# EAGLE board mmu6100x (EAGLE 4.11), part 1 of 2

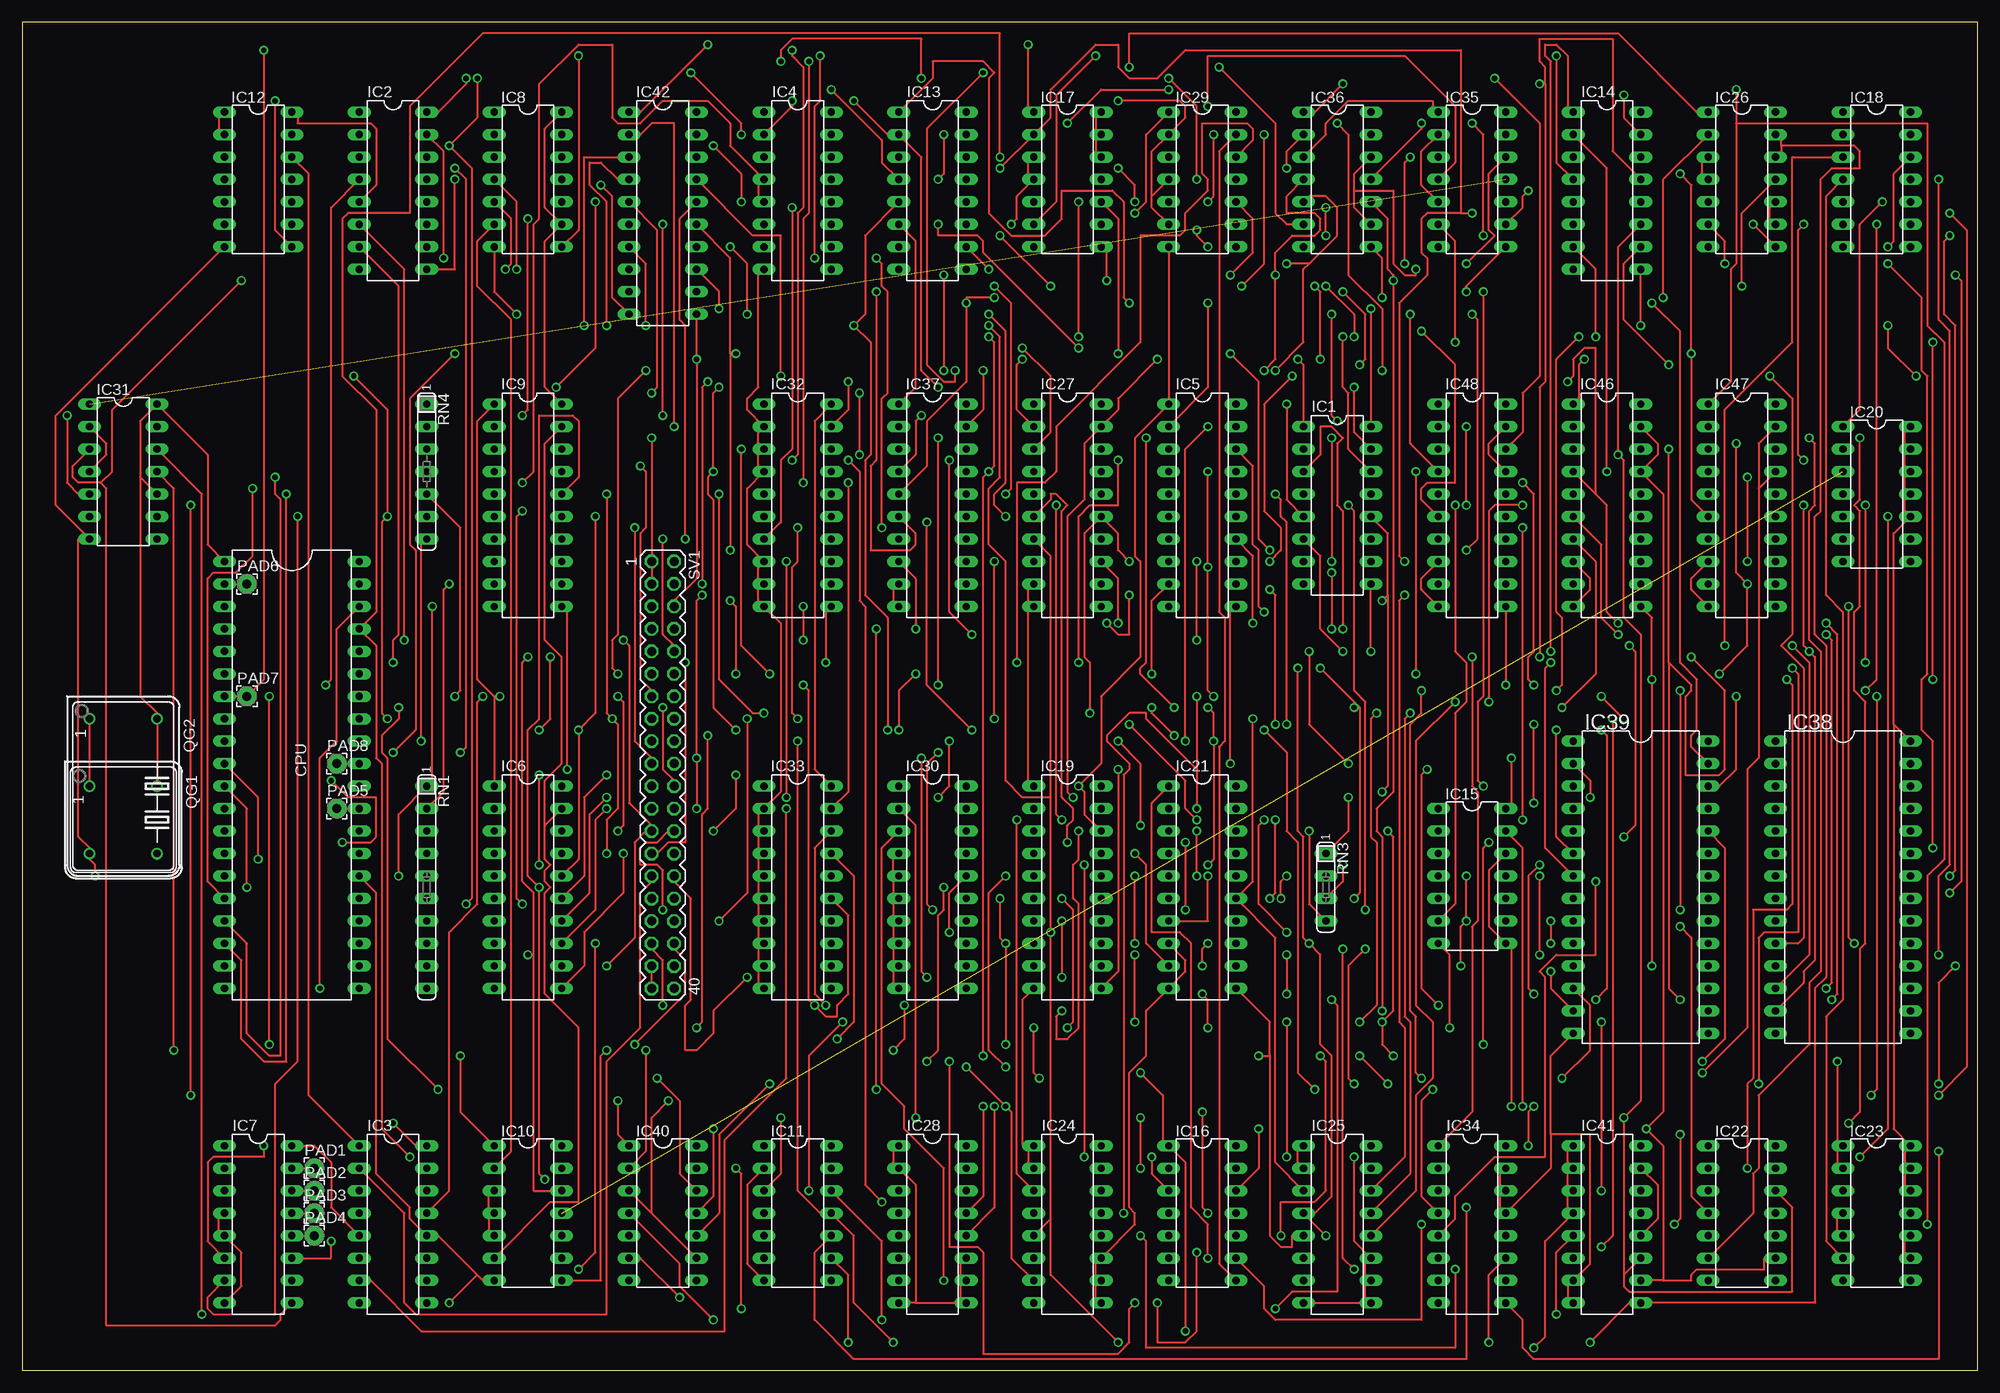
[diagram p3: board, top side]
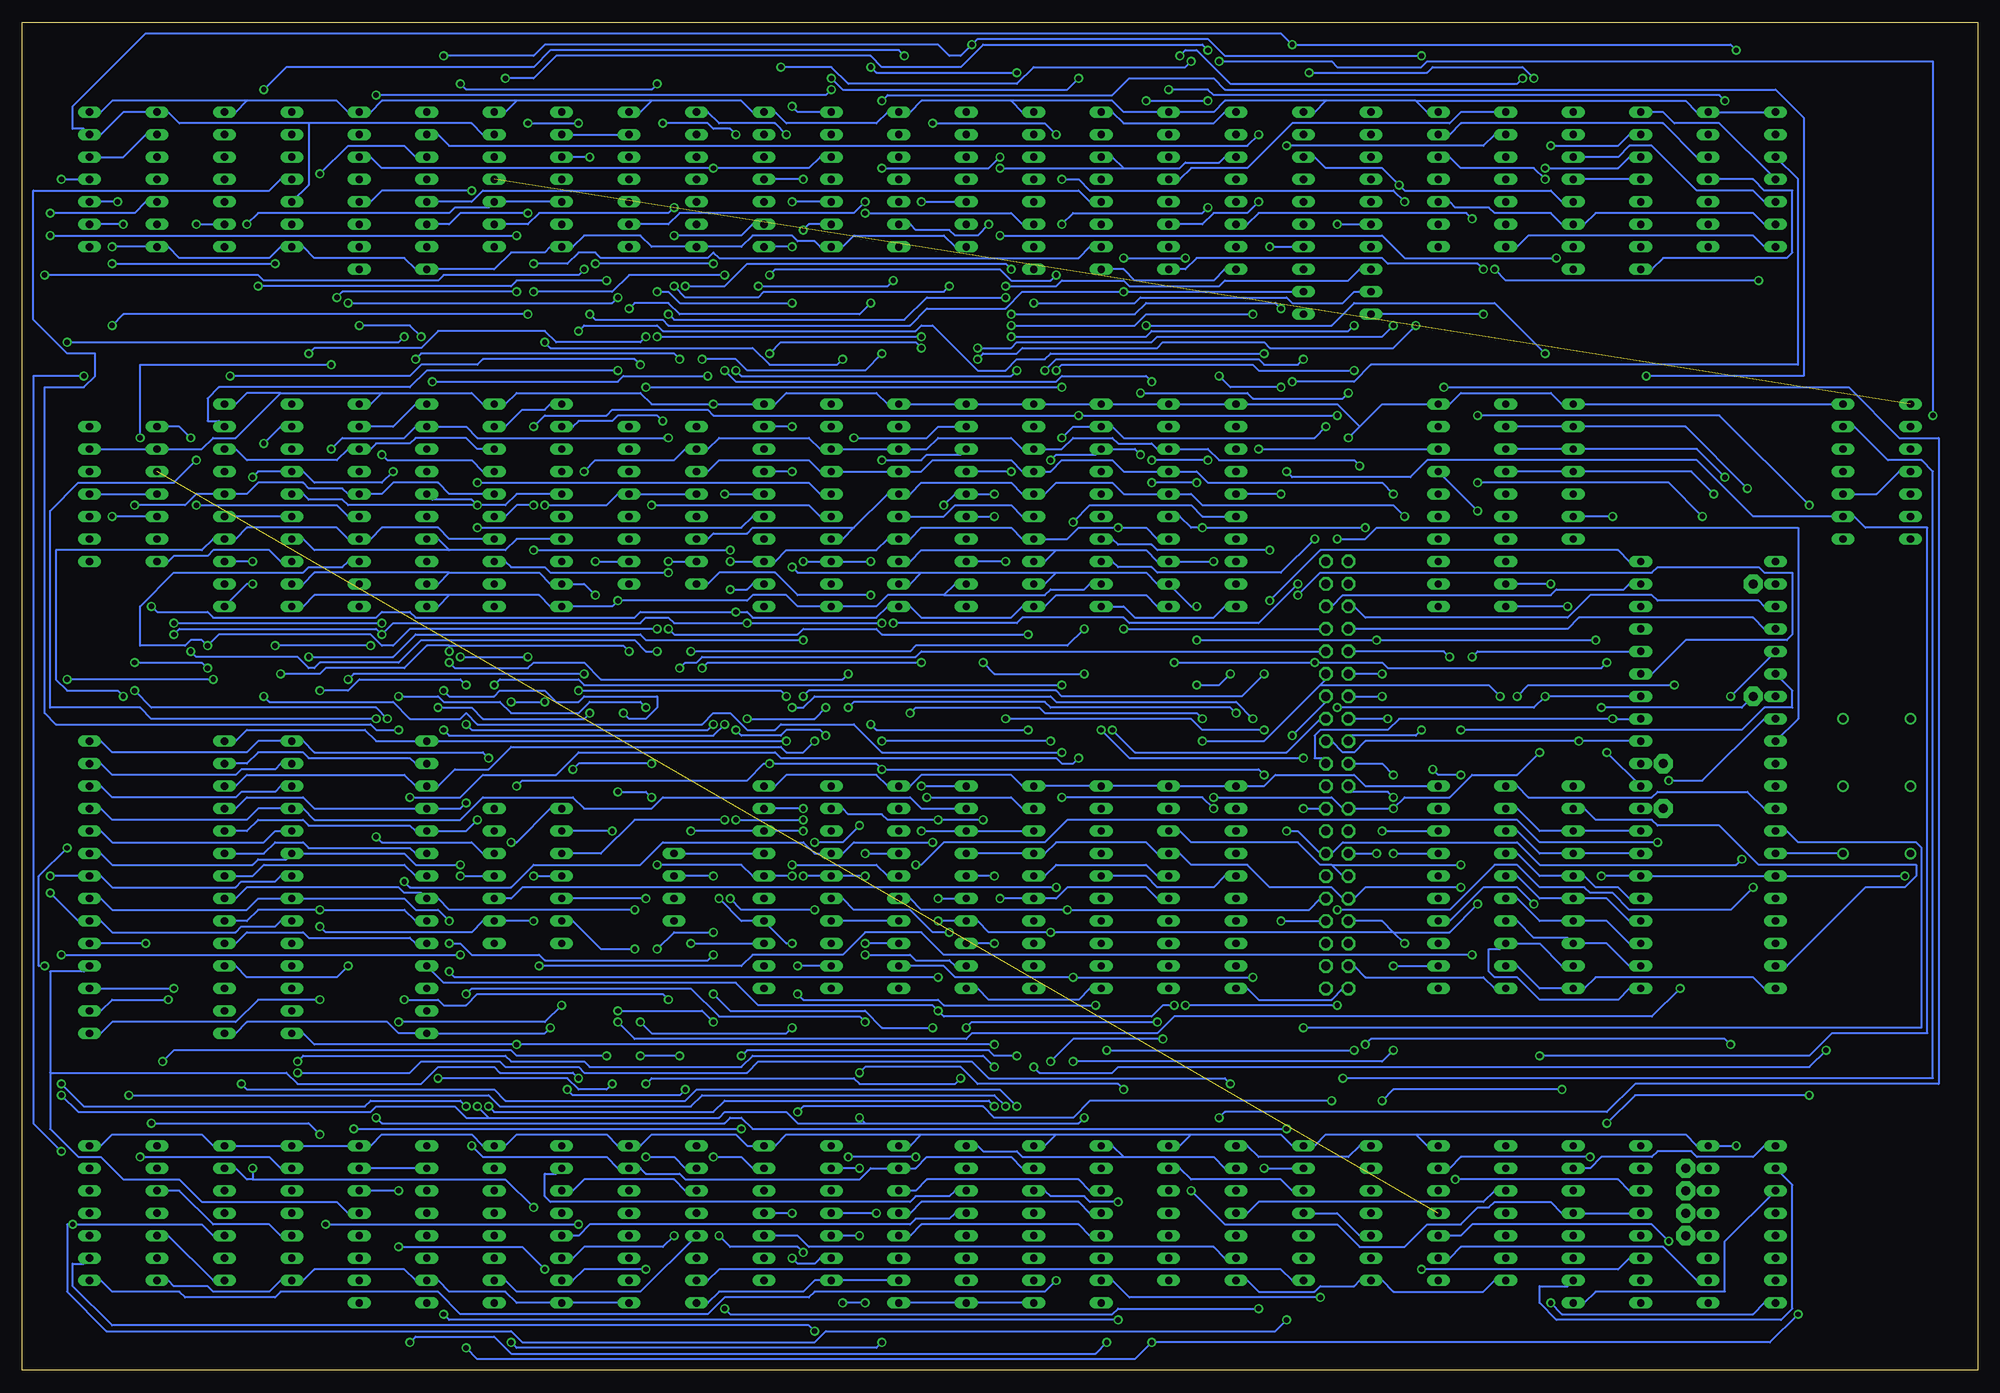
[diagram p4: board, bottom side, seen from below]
Size 220.98 x 152.4 mm. Coordinates in mm from the lower left corner, seen from the top.
Outline: 0,0 220.98,0 220.98,152.4 0,152.4 0,0
Copper layers (1*16): Top 0.035mm / dielectric 1.5mm / Bottom 0.035mm
Design rules "8mils": minimum track width 10mil, minimum drill 24mil, track to track 8mil, track to pad 8mil, pad to pad 8mil, via to via 8mil, smd to smd 8mil, copper to edge 40mil, drill to drill 10mil, minimum pad ring 10mil, minimum via ring 8mil, stop-mask expansion 0mil, vias tented up to drill 0mil, thermal gap 10mil

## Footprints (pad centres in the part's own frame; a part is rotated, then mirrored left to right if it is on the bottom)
DIL40 = drill 0.813 long: 1 -24.13,-7.62; 2 -21.59,-7.62; 3 -19.05,-7.62; 4 -16.51,-7.62; 5 -13.97,-7.62; 6 -11.43,-7.62; 7 -8.89,-7.62; 8 -6.35,-7.62; 9 -3.81,-7.62; 10 -1.27,-7.62; 11 1.27,-7.62; 12 3.81,-7.62; 13 6.35,-7.62; 14 8.89,-7.62; 15 11.43,-7.62; 16 13.97,-7.62; 17 16.51,-7.62; 18 19.05,-7.62; 19 21.59,-7.62; 20 24.13,-7.62; 21 24.13,7.62; 22 21.59,7.62; 23 19.05,7.62; 24 16.51,7.62; 25 13.97,7.62; 26 11.43,7.62; 27 8.89,7.62; 28 6.35,7.62; 29 3.81,7.62; 30 1.27,7.62; 31 -1.27,7.62; 32 -3.81,7.62; 33 -6.35,7.62; 34 -8.89,7.62; 35 -11.43,7.62; 36 -13.97,7.62; 37 -16.51,7.62; 38 -19.05,7.62; 39 -21.59,7.62; 40 -24.13,7.62
DIL16 = drill 0.813 long: 1 -8.89,-3.81; 2 -6.35,-3.81; 3 -3.81,-3.81; 4 -1.27,-3.81; 5 1.27,-3.81; 6 3.81,-3.81; 7 6.35,-3.81; 8 8.89,-3.81; 9 8.89,3.81; 10 6.35,3.81; 11 3.81,3.81; 12 1.27,3.81; 13 -1.27,3.81; 14 -3.81,3.81; 15 -6.35,3.81; 16 -8.89,3.81
DIL20 = drill 0.813 long: 1 -11.43,-3.81; 2 -8.89,-3.81; 3 -6.35,-3.81; 4 -3.81,-3.81; 5 -1.27,-3.81; 6 1.27,-3.81; 7 3.81,-3.81; 8 6.35,-3.81; 9 8.89,-3.81; 10 11.43,-3.81; 11 11.43,3.81; 12 8.89,3.81; 13 6.35,3.81; 14 3.81,3.81; 15 1.27,3.81; 16 -1.27,3.81; 17 -3.81,3.81; 18 -6.35,3.81; 19 -8.89,3.81; 20 -11.43,3.81
DIL14 = drill 0.813 long: 1 -7.62,-3.81; 2 -5.08,-3.81; 3 -2.54,-3.81; 4 0,-3.81; 5 2.54,-3.81; 6 5.08,-3.81; 7 7.62,-3.81; 8 7.62,3.81; 9 5.08,3.81; 10 2.54,3.81; 11 0,3.81; 12 -2.54,3.81; 13 -5.08,3.81; 14 -7.62,3.81
DIL28-6 = drill 0.813 long: 1 -16.51,-7.62; 2 -13.97,-7.62; 3 -11.43,-7.62; 4 -8.89,-7.62; 5 -6.35,-7.62; 6 -3.81,-7.62; 7 -1.27,-7.62; 8 1.27,-7.62; 9 3.81,-7.62; 10 6.35,-7.62; 11 8.89,-7.62; 12 11.43,-7.62; 13 13.97,-7.62; 14 16.51,-7.62; 15 16.51,7.62; 16 13.97,7.62; 17 11.43,7.62; 18 8.89,7.62; 19 6.35,7.62; 20 3.81,7.62; 21 1.27,7.62; 22 -1.27,7.62; 23 -3.81,7.62; 24 -6.35,7.62; 25 -8.89,7.62; 26 -11.43,7.62; 27 -13.97,7.62; 28 -16.51,7.62
2,15/1,0 = drill 1.016 pad 2.159 octagon: 1 0,0
DIL08S = drill 0.813 round: 1 -3.81,-3.81; 4 3.81,-3.81; 5 3.81,3.81; 8 -3.81,3.81
DIL14S = drill 0.813 round: 1 -7.62,-3.81; 7 7.62,-3.81; 8 7.62,3.81; 14 -7.62,3.81
SIL10 = drill 0.813 long: 1 -11.43,0; 2 -8.89,0; 3 -6.35,0; 4 -3.81,0; 5 -1.27,0; 6 1.27,0; 7 3.81,0; 8 6.35,0; 9 8.89,0; 10 11.43,0
SIL4 = drill 0.813 long: 1 -3.81,0; 2 -1.27,0; 3 1.27,0; 4 3.81,0
SIL7 = drill 0.813 long: 1 -7.62,0; 2 -5.08,0; 3 -2.54,0; 4 0,0; 5 2.54,0; 6 5.08,0; 7 7.62,0
MA20-2 = drill 1.016 octagon: 1 -24.13,-1.27; 2 -24.13,1.27; 3 -21.59,-1.27; 4 -21.59,1.27; 5 -19.05,-1.27; 6 -19.05,1.27; 7 -16.51,-1.27; 8 -16.51,1.27; 9 -13.97,-1.27; 10 -13.97,1.27; 11 -11.43,-1.27; 12 -11.43,1.27; 13 -8.89,-1.27; 14 -8.89,1.27; 15 -6.35,-1.27; 16 -6.35,1.27; 17 -3.81,-1.27; 18 -3.81,1.27; 19 -1.27,-1.27; 20 -1.27,1.27; 21 1.27,-1.27; 22 1.27,1.27; 23 3.81,-1.27; 24 3.81,1.27; 25 6.35,-1.27; 26 6.35,1.27; 27 8.89,-1.27; 28 8.89,1.27; 29 11.43,-1.27; 30 11.43,1.27; 31 13.97,-1.27; 32 13.97,1.27; 33 16.51,-1.27; 34 16.51,1.27; 35 19.05,-1.27; 36 19.05,1.27; 37 21.59,-1.27; 38 21.59,1.27; 39 24.13,-1.27; 40 24.13,1.27

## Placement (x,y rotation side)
CPU  IM6100  [DIL40]  30.48,67.31 270 top
IC1  74LS75N  [DIL16]  148.59,97.79 270 top
IC2  74LS75N  [DIL16]  41.91,133.35 270 top
IC3  74LS75N  [DIL16]  41.91,16.51 270 top
IC4  74HCT138N  [DIL16]  87.63,133.35 270 top
IC5  74LS373N  [DIL20]  133.35,97.79 270 top
IC6  74LS245N  [DIL20]  57.15,54.61 270 top
IC7  74HCT138N  [DIL16]  26.67,16.51 270 top
IC8  [DIL14]  57.15,134.62 270 top
IC9  74LS245N  [DIL20]  57.15,97.79 270 top
IC10  74HCT00N  [DIL14]  57.15,17.78 270 top
IC11  74LS74N  [DIL14]  87.63,17.78 270 top
IC12  74LS30N  [DIL14]  26.67,134.62 270 top
IC13  74HCT138N  [DIL16]  102.87,133.35 270 top
IC14  74HCT138N  [DIL16]  179.07,133.35 270 top
IC15  74HCT08N  [DIL14]  163.83,55.88 270 top
IC16  74LS32N  [DIL14]  133.35,17.78 270 top
IC17  74LS32N  [DIL14]  118.11,134.62 270 top
IC18  74LS74N  [DIL14]  209.55,134.62 270 top
IC19  74LS373N  [DIL20]  118.11,54.61 270 top
IC20  74LS74N  [DIL14]  209.55,99.06 270 top
IC21  74LS241N  [DIL20]  133.35,54.61 270 top
IC22  [DIL14]  194.31,17.78 270 top
IC23  74HCT00N  [DIL14]  209.55,17.78 270 top
IC24  74LS173N  [DIL16]  118.11,16.51 270 top
IC25  74LS173N  [DIL16]  148.59,16.51 270 top
IC26  74HCT00N  [DIL14]  194.31,134.62 270 top
IC27  74LS245N  [DIL20]  118.11,97.79 270 top
IC28  74LS173N  [DIL16]  102.87,16.51 270 top
IC29  74LS07N  [DIL14]  133.35,134.62 270 top
IC30  74LS245N  [DIL20]  102.87,54.61 270 top
IC31  74LS74N  [DIL14]  11.43,101.6 270 top
IC32  74LS245N  [DIL20]  87.63,97.79 270 top
IC33  74LS245N  [DIL20]  87.63,54.61 270 top
IC34  74LS157N  [DIL16]  163.83,16.51 270 top
IC35  74LS32N  [DIL14]  163.83,134.62 270 top
IC36  74HCT08N  [DIL14]  148.59,134.62 270 top
IC37  74LS245N  [DIL20]  102.87,97.79 270 top
IC38  [DIL28-6]  205.74,54.61 270 top
IC39  [DIL28-6]  182.88,54.61 270 top
IC40  74LS11N  [DIL14]  72.39,17.78 270 top
IC41  74LS151N  [DIL16]  179.07,16.51 270 top
IC42  74LS273N  [DIL20]  72.39,130.81 270 top
IC46  74LS244N  [DIL20]  179.07,97.79 270 top
IC47  74LS244N  [DIL20]  194.31,97.79 270 top
IC48  74LS244N  [DIL20]  163.83,97.79 270 top
PAD1  [2,15/1,0]  33.02,22.86 0 top
PAD2  [2,15/1,0]  33.02,20.32 0 top
PAD3  [2,15/1,0]  33.02,17.78 0 top
PAD4  [2,15/1,0]  33.02,15.24 0 top
PAD5  [2,15/1,0]  35.56,63.5 0 top
PAD6  [2,15/1,0]  25.4,88.9 0 top
PAD7  [2,15/1,0]  25.4,76.2 0 top
PAD8  [2,15/1,0]  35.56,68.58 0 top
QG1  [DIL08S]  11.43,62.23 270 top
QG2  [DIL14S]  11.43,66.04 270 top
RN1  100K  [SIL10]  45.72,54.61 270 top
RN3  100K  [SIL4]  147.32,54.61 270 top
RN4  [SIL7]  45.72,101.6 270 top
SV1  [MA20-2]  72.39,67.31 270 top

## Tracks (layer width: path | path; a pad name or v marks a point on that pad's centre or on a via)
00\  (via drill 0.61)
  Top 0.254: v28.57,143.51 28.57,128.91 IC12.8 | v91.44,144.78 97.16,139.06 97.16,136.53 IC13.4
  Bottom 0.254: v28.57,143.51 29.21,144.15 86.36,144.15 87,144.78 v91.44,144.78
2X\  (via drill 0.61)
  Top 0.254: v62.87,148.59 62.87,128.91 IC8.8 | v113.67,149.86 113.67,142.88 IC17.1 | v173.35,148.59 173.35,136.53 IC14.4
  Bottom 0.254: v62.87,148.59 85.09,148.59 87,150.5 113.03,150.5 v113.67,149.86 114.94,148.59 116.2,148.59 117.47,149.86 161.93,149.86 163.19,148.59 v173.35,148.59
AND\
  Top 0.254: IC7.15 PAD1.1
BFLD0
  Bottom 0.254: IC28.5 100.33,15.24 101.6,16.51 119.38,16.51 120.65,15.24 IC24.12
BFLD1
  Bottom 0.254: IC28.4 100.33,17.78 101.6,19.05 119.38,19.05 120.65,17.78 IC24.13
BFLD2
  Bottom 0.254: IC28.3 100.33,20.32 101.6,21.59 118.75,21.59 120.02,20.32 IC24.14
BFLOAD  (via drill 0.61)
  Top 0.254: v74.3,8.26 69.85,12.7 IC40.6
  Bottom 0.254: v74.3,8.26 95.89,8.26 97.79,10.16 IC28.7
BMUX0  (via drill 0.61)
  Top 0.254: v109.86,29.84 109.86,18.41 IC28.12 | v208.91,31.11 209.55,31.75 v209.55,76.2
  Bottom 0.254: IC48.14 172.72,93.98 173.99,95.25 180.34,95.25 181.61,93.98 IC46.14 184.15,93.98 185.42,95.25 195.58,95.25 196.85,93.98 IC47.14 199.39,93.98 200.66,92.71 217.17,92.71 217.17,78.11 215.9,76.83 210.19,76.83 v209.55,76.2 | v109.86,29.84 111.12,31.11 144.15,31.11 145.41,29.84 167,29.84 168.28,31.11 v208.91,31.11
BMUX1  (via drill 0.61)
  Top 0.254: v108.58,29.84 108.58,19.68 IC28.13 | v196.22,32.38 196.22,48.9 196.85,49.53 200.66,49.53 200.66,78.74 v200.03,79.38 | v208.28,97.79 v208.28,80.01
  Bottom 0.254: IC48.16 172.72,99.06 173.99,100.33 179.07,100.33 180.34,99.06 IC46.16 184.15,99.06 184.78,99.69 188.59,99.69 189.23,100.33 194.31,100.33 195.58,99.06 IC47.16 201.29,99.06 202.56,97.79 v208.28,97.79 | v108.58,29.84 110.49,31.75 144.78,31.75 146.05,30.48 166.37,30.48 167.64,31.75 195.58,31.75 v196.22,32.38 | v200.03,79.38 200.66,80.01 v208.28,80.01
BMUX2  (via drill 0.61)
  Top 0.254: v97.16,19.05 95.25,20.95 95.25,86.36 94.61,87 94.61,101.6 v93.34,102.87 | v87,102.87 87.63,103.5 87.63,130.81 88.27,131.44 88.27,147.32 87,148.59 v87,149.22 | v166.37,146.05 171.45,140.97 171.45,112.39 169.54,110.49 169.54,106.05 IC48.18
  Bottom 0.254: IC47.18 196.85,104.14 195.58,102.87 185.42,102.87 184.15,104.14 IC46.18 181.61,104.14 180.97,104.78 177.16,104.78 176.53,105.41 170.81,105.41 169.54,104.14 IC48.18 | v97.16,19.05 100.33,19.05 100.97,19.68 104.78,19.68 105.41,20.32 IC28.14 | v87,102.87 v93.34,102.87 | v87,149.22 87.63,149.86 112.39,149.86 114.94,147.32 123.83,147.32 125.09,148.59 160.66,148.59 163.19,146.05 v166.37,146.05
C0\  (via drill 0.61)
  Top 0.254: v45.09,71.12 45.09,93.34 RN4.7
  Bottom 0.254: CPU.32 v45.09,71.12 69.22,71.12 70.48,69.85 71.75,69.85 73.03,71.12 SV1.18
C1\  (via drill 0.61)
  Top 0.254: 127.64,132.72 127.64,131.44 IC29.6 | 127.64,132.72 IC29.4 | 127.64,132.72 127.64,137.79 IC29.2 131.44,141.6 131.44,142.88 130.81,143.51 v123.83,143.51 | v133.99,127 132.72,128.27 v132.72,128.91 | v41.27,73.66 40.64,74.3 40.64,95.89 v41.27,96.52 41.27,108.58 v37.47,112.39
  Bottom 0.254: v132.72,128.91 132.08,129.54 IC29.6 | v133.99,127 IC29.8 | CPU.33 v41.27,73.66 65.41,73.66 66.67,72.39 74.3,72.39 74.93,71.75 74.93,69.22 73.66,69.22 SV1.20 | v41.27,96.52 RN4.6 | v123.83,143.51 123.19,144.15 97.79,144.15 95.89,146.05 86.36,146.05 85.09,144.78 22.86,144.78 19.68,141.6 19.68,112.39 v37.47,112.39
C2\  (via drill 0.61)
  Top 0.254: v48.9,76.2 49.53,76.83 49.53,95.25 RN4.5 | v72.39,74.93 72.39,67.94 73.66,66.67 SV1.22
  Bottom 0.254: CPU.34 v48.9,76.2 50.16,74.93 v72.39,74.93
CAF\  (via drill 0.61)
  Top 0.254: v163.19,125.09 166.37,128.27 165.74,128.91 165.74,135.25 IC35.12
  Bottom 0.254: v163.19,125.09 159.38,125.09 158.12,126.36 156.21,126.36 155.57,125.73 143.51,125.73 142.88,126.36 142.24,125.73 101.6,125.73 100.33,127 IC13.7
CDF\  (via drill 0.61)
  Top 0.254: v84.45,32.38 78.74,26.67 78.74,17.78 IC40.10 | v189.87,33.66 194.94,38.73 194.94,67.94 196.22,69.22 196.22,99.69 | 196.22,99.69 IC47.17 | 196.22,99.69 196.22,104.78 IC47.19 | v122.56,123.19 122.56,126.36 IC17.8 | v137.79,122.56 140.34,125.09 v140.34,139.7 | v148.59,140.97 149.86,139.7 149.86,123.83 153.67,120.02 v153.67,113.03
  Bottom 0.254: v84.45,32.38 85.09,33.02 111.76,33.02 113.67,34.92 137.79,34.92 139.06,33.66 157.48,33.66 158.12,34.29 166.37,34.29 167,34.92 175.9,34.92 177.16,33.66 v189.87,33.66 | v122.56,123.19 123.19,122.56 v137.79,122.56 | v140.34,139.7 140.97,140.34 142.88,140.34 143.51,140.97 v148.59,140.97 | v153.67,113.03 175.26,113.03 177.16,111.12 198.75,111.12 200.03,109.86 200.03,107.31 198.75,107.31 IC47.19
CIF\  (via drill 0.61)
  Top 0.254: v193.68,144.78 193.68,140.97 | 193.68,140.97 193.68,125.09 193.04,124.46 193.04,111.76 IC47.1 | v121.28,148.59 116.84,144.15 116.84,132.08 IC17.6 | v78.11,5.71 74.3,9.53 74.3,12.06 IC40.4 | 193.68,140.97 215.26,140.97 215.26,118.11 217.17,116.2 217.17,57.78 215.26,55.88 v215.26,16.51
  Bottom 0.254: v193.68,144.78 191.13,147.32 163.19,147.32 161.29,149.22 121.92,149.22 v121.28,148.59 | v78.11,5.71 79.38,4.45 130.18,4.45 131.44,3.17 164.47,3.17 165.74,4.45 211.46,4.45 215.9,8.89 215.9,16.51 v215.26,16.51 200.66,16.51 199.39,15.24 IC22.10
CINT\  (via drill 0.61)
  Top 0.254: v85.72,28.57 85.72,22.23 IC11.3 | v60.33,111.12 64.77,115.57 v64.77,132.08 | v103.5,134.62 104.14,135.25 v104.14,139.7 | v118.11,140.97 121.92,144.78 v129.54,144.78 | v180.97,144.15 180.97,141.6 IC14.15
  Bottom 0.254: v85.72,28.57 85.09,29.21 41.91,29.21 38.73,32.38 4.45,32.38 4.45,105.41 8.89,105.41 14.61,111.12 v60.33,111.12 | v64.77,132.08 66.04,133.35 100.33,133.35 101.6,134.62 v103.5,134.62 | v104.14,139.7 105.41,140.97 v118.11,140.97 | v129.54,144.78 130.18,144.15 v180.97,144.15
CPREQ\  (via drill 0.61)
  Top 0.254: v27.94,36.83 v27.94,76.2 | v69.22,36.83 74.93,42.55 74.93,46.35 73.66,47.62 SV1.36
  Bottom 0.254: v27.94,36.83 28.57,37.47 68.58,37.47 v69.22,36.83 | v27.94,76.2 CPU.5
CPSEL
  Bottom 0.254: IC22.5 191.77,15.24 193.04,16.51 199.39,16.51 203.2,20.32 IC23.3
CPSEL\  (via drill 0.61)
  Top 0.254: IC23.2 205.1,23.5 205.1,24.77 IC23.1 205.1,26.04 v205.1,34.92 | v33.66,43.18 33.66,69.22 35.56,71.12 35.56,83.82 CPU.38 | v154.31,60.96 154.94,60.33 154.94,40.64 v153.67,39.37 153.67,36.83 v154.94,35.56
  Bottom 0.254: v33.66,43.18 36.83,40.01 90.81,40.01 92.71,38.1 113.67,38.1 114.3,37.47 151.76,37.47 v153.67,39.37 | v154.31,60.96 IC15.2 | v205.1,34.92 203.84,36.2 165.74,36.2 165.1,35.56 v154.94,35.56
CPUDX0  (via drill 0.61)
  Top 0.254: v26.04,99.69 26.04,92.08 24.13,90.17 21.59,90.17 20.95,89.53 20.95,55.24 CPU.16
  Bottom 0.254: v26.04,99.69 33.02,106.68 RN4.2 IC9.2
CPUDX1  (via drill 0.61)
  Top 0.254: v28.57,100.97 28.57,99.06 29.21,98.42 29.21,35.56 27.94,35.56 25.4,38.1 25.4,48.26 CPU.17
  Bottom 0.254: v28.57,100.97 31.75,104.14 RN4.3 IC9.3
CPUDX2  (via drill 0.61)
  Top 0.254: v29.84,99.06 29.84,34.92 27.3,34.92 24.77,37.47 24.77,46.35 CPU.18
  Bottom 0.254: v29.84,99.06 32.38,101.6 RN4.4 IC9.4
CPUDX3  (via drill 0.61)
  Top 0.254: v48.26,88.9 47.62,88.27 47.62,65.41 RN1.2
  Bottom 0.254: CPU.19 21.59,45.72 12.7,54.61 8.26,54.61 6.99,55.88 6.99,57.15 24.77,57.15 29.21,61.59 36.2,61.59 36.83,62.23 43.18,62.23 44.45,63.5 RN1.2 | v48.26,88.9 IC9.9
CPUDX4
  Bottom 0.254: CPU.20 24.13,43.18 25.4,44.45 43.18,44.45 44.45,43.18 RN1.10 49.53,43.18 52.07,45.72 IC6.9
CPUDX5
  Bottom 0.254: CPU.21 39.37,43.18 40.64,41.91 49.53,41.91 52.07,44.45 54.61,44.45 55.24,45.09 55.24,47.62 53.98,47.62 IC6.8 49.53,48.26 46.99,45.72 RN1.9
CPUDX6
  Bottom 0.254: CPU.22 39.37,45.72 41.91,48.26 RN1.8 46.35,48.9 50.16,48.9 52.07,50.8 IC6.7
CPUDX7
  Bottom 0.254: CPU.23 39.37,48.26 41.91,50.8 RN1.7 49.53,50.8 52.07,53.34 IC6.6
CPUDX8
  Bottom 0.254: CPU.24 39.37,50.8 41.91,53.34 RN1.6 49.53,53.34 52.07,55.88 IC6.5
CPUDX9
  Bottom 0.254: CPU.25 39.37,53.34 40.64,54.61 43.18,54.61 44.45,55.88 RN1.5 49.53,55.88 52.07,58.42 IC6.4
CPUDX10
  Bottom 0.254: CPU.27 RN1.4 49.53,58.42 52.07,60.96 IC6.3
CPUDX11
  Bottom 0.254: CPU.28 RN1.3 49.53,60.96 52.07,63.5 IC6.2
CPUINTREQ\  (via drill 0.61)
  Top 0.254: v34.92,66.67 36.83,64.77 40.01,64.77 40.01,60.33 39.37,59.69 v36.2,59.69 | v120.02,57.15 v120.02,24.13 | v127.64,24.13 127.64,22.23 IC16.3
  Bottom 0.254: v34.92,66.67 31.11,66.67 24.13,73.66 CPU.8 | v36.2,59.69 49.53,59.69 52.07,62.23 102.87,62.23 105.41,59.69 116.84,59.69 119.38,57.15 v120.02,57.15 | v120.02,24.13 v127.64,24.13
CUF\  (via drill 0.61)
  Top 0.254: v70.48,36.2 70.48,24.77 IC40.2 | v98.42,36.2 99.69,37.47 v99.69,41.27 | v133.35,42.55 133.99,41.91 v133.99,38.73 | v151.13,39.37 153.03,41.27 153.03,59.69 152.4,60.33 152.4,73.66 v153.03,74.3 | v173.35,76.83 173.99,77.47 173.99,85.09 173.35,85.72 173.35,114.3 v175.9,116.84 | v182.88,118.11 IC14.9
  Bottom 0.254: v98.42,36.2 v70.48,36.2 | v99.69,41.27 116.84,41.27 117.47,41.91 132.72,41.91 v133.35,42.55 | v133.99,38.73 134.62,38.1 149.86,38.1 v151.13,39.37 | v153.03,74.3 152.4,73.66 150.5,73.66 149.22,74.93 149.22,76.2 157.48,76.2 158.12,75.56 160.66,75.56 161.93,76.83 167,76.83 167.64,76.2 172.72,76.2 v173.35,76.83 | v175.9,116.84 177.16,118.11 v182.88,118.11
DATAF  (via drill 0.61)
  Top 0.254: v80.01,87 80.64,86.36 v80.64,78.74 | 132.72,67.94 v132.72,63.5 | v132.72,76.2 132.72,67.94 | v124.46,17.78 124.46,67.31 125.09,67.94 125.09,68.58 122.56,71.12 122.56,71.75 125.09,74.3 127,74.3 127,73.66 132.72,67.94
  Bottom 0.254: v80.01,87 74.3,92.71 40.64,92.71 39.37,91.44 CPU.40 | v80.64,78.74 83.19,76.2 103.5,76.2 104.14,76.83 132.08,76.83 v132.72,76.2 | v132.72,63.5 IC21.19 | v124.46,17.78 IC16.4
DCA\
  Top 0.254: IC7.12 PAD4.1
DEVINTREQ  (via drill 0.61)
  Top 0.254: v104.14,10.16 104.14,22.86 99.69,27.3 99.69,29.84 97.16,32.38 97.16,59.05 IC30.3
  Bottom 0.254: v104.14,10.16 105.41,8.89 131.44,8.89 132.08,8.26 141.6,8.26 143.51,6.35 171.45,6.35 173.99,8.89 191.77,8.89 192.41,8.26 202.56,8.26 203.2,8.89 210.82,8.89 212.09,10.16 IC23.8
DEVINTREQ\  (via drill 0.61)
  Top 0.254: IC23.9 212.72,13.34 212.72,14.61 IC23.10 | v131.44,4.45 131.44,23.5 IC16.1 128.91,26.04 128.91,31.11 v126.36,33.66 | v96.52,31.75 v96.52,83.82
  Bottom 0.254: v131.44,4.45 132.08,5.08 210.82,5.08 215.26,9.53 215.26,12.06 214,12.06 IC23.9 | v96.52,31.75 97.16,32.38 113.03,32.38 114.94,34.29 125.73,34.29 v126.36,33.66 | v96.52,83.82 SV1.8
DEVSEL\  (via drill 0.61)
  Top 0.254: v41.91,69.85 44.45,72.39 44.45,92.71 43.81,93.34 43.81,109.86 v48.9,114.94 | IC13.5 95.25,128.27 95.25,119.38 v93.98,118.11 95.89,116.2 95.89,103.5 95.25,102.87 95.25,87.63 97.79,85.09 v97.79,72.39
  Bottom 0.254: v48.9,114.94 54.61,120.65 70.48,120.65 73.03,118.11 v93.98,118.11 | v41.91,69.85 CPU.30 | IC14.5 170.18,132.08 168.91,133.35 101.6,133.35 100.33,132.08 IC13.5 | v97.79,72.39 95.25,69.85 78.11,69.85 74.3,73.66 SV1.16
DFLD0  (via drill 0.61)
  Top 0.254: 140.97,35.56 140.97,15.24 142.24,13.97 143.51,13.97 143.51,15.24 IC25.5 | 140.97,35.56 140.97,39.37 IC21.11 | v70.48,118.11 70.48,125.09 IC42.7 | v109.22,116.84 109.86,116.2 109.86,102.23 v109.22,101.6 108.58,100.97 v108.58,35.56 | v139.7,35.56 140.97,35.56
  Bottom 0.254: IC25.5 151.13,8.89 165.1,8.89 166.37,10.16 IC34.10 | v70.48,118.11 71.12,117.47 93.34,117.47 93.98,116.84 v109.22,116.84 | v109.22,101.6 IC27.4 | v139.7,35.56 139.06,36.2 111.76,36.2 111.12,35.56 v108.58,35.56
DFLD1  (via drill 0.61)
  Top 0.254: v147.32,15.24 IC25.4 146.05,17.78 147.96,19.68 147.96,35.56 146.69,36.83 146.69,46.99 v145.41,48.26 144.78,48.9 144.78,60.33 144.15,60.96 v144.15,79.38 | v66.04,118.11 66.04,132.08 64.14,133.99 64.14,136.53 65.41,136.53 67.31,134.62 IC42.4 | v113.03,115.57 116.2,112.39 116.2,106.05 IC27.3 | v119.38,80.01 119.38,96.52 120.65,97.79 123.83,97.79 v123.83,102.87
  Bottom 0.254: v147.32,15.24 148.59,13.97 157.48,13.97 158.75,12.7 IC34.6 | v145.41,48.26 IC21.13 | v66.04,118.11 67.31,116.84 92.71,116.84 93.34,116.2 108.58,116.2 109.22,115.57 v113.03,115.57 | v144.15,79.38 143.51,80.01 v119.38,80.01 | v123.83,102.87 119.38,102.87 118.75,103.5 114.94,103.5 IC27.3
DFLD2  (via drill 0.61)
  Top 0.254: IC25.3 141.6,23.5 141.6,48.9 IC21.15 139.06,55.24 v139.06,73.66 | v63.5,118.11 63.5,137.16 IC42.3 | v113.03,114.3 112.39,113.67 112.39,108.58 IC27.2 | v130.18,74.93 126.36,78.74 126.36,79.38 127,80.01 v127,105.41
  Bottom 0.254: IC25.3 146.05,20.32 147.32,21.59 157.48,21.59 158.75,20.32 IC34.3 | v63.5,118.11 66.04,115.57 80.01,115.57 80.64,116.2 92.08,116.2 92.71,115.57 107.95,115.57 108.58,114.94 112.39,114.94 v113.03,114.3 | v139.06,73.66 131.44,73.66 v130.18,74.93 | v127,105.41 118.75,105.41 117.47,106.68 IC27.2
DFLOAD
  Bottom 0.254: IC40.8 77.47,10.16 78.74,11.43 142.24,11.43 143.51,10.16 IC25.7
DMAGNT
  Bottom 0.254: CPU.3 24.13,86.36 24.77,87 36.2,87 36.83,87.63 43.81,87.63 46.35,85.09 69.22,85.09 70.48,86.36 SV1.5
DMAREQ\
  Bottom 0.254: CPU.4 24.13,83.82 25.4,85.09 45.09,85.09 46.35,83.82 SV1.7
DMUX0  (via drill 0.61)
  Top 0.254: v161.93,75.56 157.48,71.12 157.48,41.27 159.38,39.37 159.38,33.02 157.48,31.11 157.48,20.32 IC25.12 | v165.74,75.56 165.74,97.16 166.37,97.79 v169.54,97.79
  Bottom 0.254: v165.74,75.56 v161.93,75.56 | v169.54,97.79 170.18,98.42 174.62,98.42 IC46.5 | v169.54,97.79 166.37,97.79 165.1,99.06 IC48.5 | v169.54,97.79 184.15,97.79 184.78,98.42 188.59,98.42 189.23,99.06 IC47.5
DMUX1  (via drill 0.61)
  Top 0.254: v156.84,74.3 156.21,73.66 156.21,40.01 156.84,39.37 156.84,22.23 IC25.13 | v173.99,74.93 177.8,78.74 177.8,91.44 IC46.7
  Bottom 0.254: v156.84,74.3 157.48,73.66 168.91,73.66 170.18,74.93 v173.99,74.93 | 172.72,92.71 166.37,92.71 165.1,93.98 IC48.7 | 172.72,92.71 173.99,93.98 IC46.7 | 172.72,92.71 187.96,92.71 189.23,93.98 IC47.7
DMUX2  (via drill 0.61)
  Top 0.254: v156.21,87.63 155.57,87 155.57,39.37 156.21,38.73 156.21,24.13 IC25.14
  Bottom 0.254: v156.21,87.63 157.48,88.9 IC48.9 161.29,88.9 162.56,90.17 172.72,90.17 | 172.72,90.17 173.99,88.9 IC46.9 | 172.72,90.17 187.96,90.17 189.23,88.9 IC47.9
DORTF\  (via drill 0.61)
  Top 0.254: IC40.9 71.12,17.78 | 71.12,17.78 IC40.3 | v133.99,17.78 133.35,18.41 v133.35,29.21 | v73.03,30.48 71.12,28.57 71.12,17.78
  Bottom 0.254: v133.35,29.21 132.72,29.84 112.39,29.84 111.12,28.57 102.23,28.57 100.33,30.48 v73.03,30.48 | v133.99,17.78 IC16.11
DX0  (via drill 0.61)
  Top 0.254: v110.49,53.34 110.49,48.9 v111.12,48.26 v111.12,36.83 | v81.28,104.14 81.28,81.92 v84.45,78.74 | v88.27,77.47 88.9,76.83 88.9,41.91 v89.53,41.27 90.81,40.01 92.08,40.01 92.08,41.27 93.34,42.55 93.34,51.44 IC33.15 | v165.74,59.69 165.1,59.05 v165.1,36.83 | v72.39,41.27 72.39,46.35 71.12,47.62 SV1.35
  Bottom 0.254: IC33.15 92.71,53.34 93.98,54.61 102.87,54.61 104.14,53.34 IC30.15 v110.49,53.34 | v111.12,48.26 IC19.8 | v84.45,78.74 85.72,77.47 v88.27,77.47 | v81.28,104.14 IC9.18 | v111.12,36.83 v165.1,36.83 187.96,36.83 189.23,38.1 IC39.15 | v165.74,59.69 165.1,59.69 161.29,63.5 IC15.1 | v72.39,41.27 v89.53,41.27
DX1  (via drill 0.61)
  Top 0.254: v62.87,11.43 64.77,13.34 v64.77,48.26 | v56.52,97.16 55.88,96.52 55.88,53.34 v56.52,52.7 | v172.72,45.09 172.72,43.18 IC39.13 | v117.47,50.8 v117.47,44.45 | v104.78,49.53 104.78,53.98 IC30.16
  Bottom 0.254: IC33.16 92.71,55.88 93.98,57.15 104.14,57.15 105.41,55.88 IC30.16 | v62.87,11.43 40.64,11.43 39.37,12.7 IC3.6 | 66.04,49.53 67.31,50.8 SV1.33 | v64.77,48.26 66.04,49.53 | 66.04,49.53 v104.78,49.53 111.76,49.53 113.03,50.8 IC19.7 v117.47,50.8 | v56.52,52.7 59.69,49.53 66.04,49.53 | v56.52,97.16 IC9.17 | v172.72,45.09 172.09,44.45 v117.47,44.45
DX2  (via drill 0.61)
  Top 0.254: v59.05,21.59 58.42,22.23 v58.42,54.61 57.15,55.88 57.15,72.39 58.42,73.66 58.42,107.95 62.23,107.95 62.87,107.31 62.87,100.97 IC9.16 | v173.99,33.02 177.16,36.2 177.16,41.27 IC39.12 | v151.13,35.56 v154.31,32.38 | v146.69,35.56 147.32,34.92 147.32,20.32 146.05,19.05 142.24,19.05 v142.24,15.24 | v132.72,13.34 132.72,4.45 131.44,3.17 128.27,3.17 v128.27,7.62 | v125.73,7.62 125.09,6.99 125.09,3.17 123.83,1.91 108.58,1.91 108.58,13.34 107.95,13.97 104.78,13.97 v104.78,34.92 | v92.08,37.47 93.98,39.37 93.98,55.88 IC33.17
  Bottom 0.254: v59.05,21.59 40.64,21.59 39.37,20.32 IC3.3 | v58.42,54.61 69.22,54.61 70.48,53.34 SV1.31 71.75,53.34 73.03,54.61 80.01,54.61 82.55,57.15 88.9,57.15 90.17,58.42 IC33.17 92.71,58.42 93.98,59.69 104.14,59.69 105.41,58.42 IC30.17 IC19.4 | v173.99,33.02 159.38,33.02 158.12,31.75 154.94,31.75 v154.31,32.38 | v146.69,35.56 v151.13,35.56 | v142.24,15.24 140.97,13.97 133.35,13.97 v132.72,13.34 | v125.73,7.62 v128.27,7.62 | v104.78,34.92 102.23,37.47 v92.08,37.47
DX3  (via drill 0.61)
  Top 0.254: IC3.2 43.18,17.78 43.18,7.62 44.45,6.35 66.04,6.35 66.04,34.92 69.85,38.73 69.85,53.98 71.12,55.24 SV1.29 | v90.81,41.27 89.53,42.55 89.53,59.05 IC33.18 | v61.59,67.94 61.59,85.72 IC9.11 | v58.42,57.15 v58.42,67.31 | v119.38,60.96 119.38,57.78 118.75,57.15 118.75,53.34 119.38,52.7 119.38,38.73 118.11,37.47 116.84,37.47 116.84,40.01 v117.47,40.64
  Bottom 0.254: IC30.18 IC19.3 v119.38,60.96 | 73.03,57.15 74.3,57.15 76.83,59.69 88.9,59.69 90.17,60.96 IC33.18 | 73.03,57.15 71.75,55.88 SV1.29 | v90.81,41.27 92.08,41.27 93.34,40.01 116.84,40.01 v117.47,40.64 118.11,41.27 137.79,41.27 140.34,43.81 173.35,43.81 IC39.11 | v61.59,67.94 60.96,67.31 v58.42,67.31 | 73.03,57.15 v58.42,57.15
DX4  (via drill 0.61)
  Top 0.254: v67.94,58.42 67.94,53.98 63.5,49.53 63.5,45.72 IC6.11 | v207.01,48.26 206.38,48.9 v206.38,86.36 | v41.91,80.01 41.91,82.55 42.55,83.19 42.55,122.56 IC2.7 | v90.81,80.01 90.81,85.72 IC32.11 | v140.34,85.72 139.7,86.36 139.7,92.71 139.06,93.34 139.06,102.23 IC5.18 | v74.93,80.01 74.93,59.69 73.03,59.69 71.75,58.42 SV1.27
  Bottom 0.254: SV1.27 v67.94,58.42 | IC32.11 92.71,86.36 93.98,87.63 104.14,87.63 105.41,86.36 IC37.11 107.95,86.36 109.22,85.09 119.38,85.09 120.65,86.36 IC27.11 123.19,86.36 124.46,85.09 138.43,85.09 139.06,85.72 v140.34,85.72 151.13,85.72 151.76,85.09 176.53,85.09 177.16,85.72 180.34,85.72 180.97,85.09 199.39,85.09 200.03,85.72 205.74,85.72 v206.38,86.36 | v207.01,48.26 IC38.19 | v41.91,80.01 42.55,79.38 66.67,79.38 67.31,80.01 v74.93,80.01 v90.81,80.01
DX5  (via drill 0.61)
  Top 0.254: v133.99,101.6 v133.99,90.81 133.99,76.83 v134.62,76.2 | v66.04,45.72 69.22,48.9 69.22,59.69 70.48,60.96 SV1.25 71.12,61.59 68.58,64.14 68.58,81.92 v67.94,82.55 | v43.18,82.55 43.18,124.46 IC2.6 | v88.27,86.36 v88.27,82.55 | v158.12,33.02 157.48,33.66 157.48,40.01 156.84,40.64 156.84,73.03 158.12,74.3 v158.12,76.83
  Bottom 0.254: 217.81,33.66 217.81,45.09 214,45.09 IC38.18 | 217.81,33.66 217.81,27.3 214.63,24.13 212.09,24.13 209.55,21.59 203.2,21.59 200.66,19.05 185.42,19.05 184.15,17.78 IC41.13 | 104.14,90.17 93.98,90.17 92.71,88.9 IC32.12 88.9,86.36 v88.27,86.36 | 104.14,90.17 105.41,88.9 IC37.12 | 119.38,90.17 120.65,88.9 IC27.12 | 119.38,90.17 104.14,90.17 | v133.99,90.81 133.35,90.17 119.38,90.17 | v133.99,101.6 IC5.17 | v66.04,45.72 IC6.12 | v43.18,82.55 v67.94,82.55 v88.27,82.55 | 217.81,33.66 191.13,33.66 189.87,32.38 175.9,32.38 173.99,34.29 167.64,34.29 167,33.66 158.75,33.66 v158.12,33.02 | v158.12,76.83 135.25,76.83 v134.62,76.2
DX6  (via drill 0.61)
  Top 0.254: v66.04,63.5 64.77,62.23 64.77,52.07 IC6.13 | v48.9,135.89 50.16,134.62 50.16,70.48 v49.53,69.85 | v203.84,43.18 204.47,43.81 204.47,82.55 v203.84,83.19 | v180.34,83.19 178.44,85.09 178.44,93.34 IC46.6 | v139.06,84.45 139.06,92.08 IC5.14 | v123.83,84.45 123.83,89.53 IC27.13 | v86.36,91.44 v86.36,64.77
  Bottom 0.254: v48.9,135.89 40.64,135.89 39.37,137.16 IC2.3 | v49.53,69.85 52.07,67.31 57.15,67.31 59.69,64.77 64.77,64.77 v66.04,63.5 SV1.23 71.75,63.5 73.03,64.77 v86.36,64.77 | 104.14,92.71 93.98,92.71 92.71,91.44 IC32.13 v86.36,91.44 | 104.14,92.71 105.41,91.44 IC37.13 | 104.14,92.71 119.38,92.71 120.65,91.44 IC27.13 | v203.84,83.19 203.2,83.82 180.97,83.82 v180.34,83.19 179.07,84.45 151.13,84.45 150.5,85.09 147.96,85.09 147.32,84.45 v139.06,84.45 v123.83,84.45 | IC38.17 v203.84,43.18
DX7  (via drill 0.61)
  Top 0.254: v66.04,64.77 64.14,62.87 64.14,53.98 IC6.14 | v50.16,52.7 50.8,53.34 50.8,135.89 v48.26,138.43 51.44,141.6 v51.44,146.05 | v204.47,41.91 205.1,42.55 205.1,83.19 v203.84,84.45 | v180.34,84.45 179.07,85.72 179.07,97.79 177.8,99.06 | 177.8,99.06 IC46.4 | v140.97,91.44 142.24,92.71 142.24,95.25 140.34,97.16 140.34,109.22 v143.51,112.39 | v174.62,111.76 175.26,112.39 175.26,114.3 176.53,115.57 177.8,115.57 177.8,99.06 | v90.17,148.59 90.17,143.51 89.53,142.88 v89.53,125.73 | v96.52,125.73 97.16,125.09 97.16,122.56 97.79,121.92 97.79,110.49 97.16,109.86 v97.16,95.25
  Bottom 0.254: v66.04,64.77 66.67,65.41 71.12,65.41 SV1.21 | v48.26,138.43 40.64,138.43 39.37,139.7 IC2.2 | v50.16,52.7 52.07,54.61 55.88,54.61 59.69,50.8 IC6.14 | IC32.14 92.71,93.98 93.98,95.25 v97.16,95.25 101.6,95.25 102.87,93.98 IC37.14 107.95,93.98 109.22,95.25 119.38,95.25 120.65,93.98 IC27.14 123.19,93.98 124.46,92.71 134.62,92.71 135.89,91.44 IC5.13 v140.97,91.44 | v204.47,41.91 210.82,41.91 212.09,40.64 IC38.16 | v203.84,84.45 v180.34,84.45 | v143.51,112.39 153.03,112.39 153.67,111.76 v174.62,111.76 | v51.44,146.05 52.07,145.41 84.45,145.41 88.27,149.22 89.53,149.22 v90.17,148.59 | v96.52,125.73 v89.53,125.73
DX8  (via drill 0.61)
  Top 0.254: v125.09,91.44 123.83,92.71 123.83,94.61 IC27.15 120.02,94.61 120.02,80.64 120.65,80.01 v120.65,74.3 | v66.04,67.31 63.5,64.77 63.5,55.88 IC6.15 | v69.22,95.25 69.22,71.12 71.12,69.22 SV1.19 | v87.63,73.66 87,74.3 87,90.81 87.63,91.44 v87.63,95.25 | v147.96,105.41 v147.96,91.44 | v187.32,41.91 186.06,43.18 186.06,80.01 | 186.06,80.01 v186.06,104.14 | v132.72,82.55 v132.72,91.44 | v188.59,80.64 192.41,76.83 192.41,67.94 191.77,67.31 187.96,67.31 187.96,76.2 188.59,76.83 188.59,77.47 186.06,80.01
  Bottom 0.254: v125.09,91.44 IC5.8 v132.72,91.44 | IC37.15 107.95,96.52 109.22,97.79 115.57,97.79 116.84,96.52 IC27.15 | v66.04,67.31 67.31,68.58 SV1.19 | v69.22,95.25 v87.63,95.25 88.9,95.25 90.17,96.52 IC32.15 | v120.65,74.3 120.02,74.93 106.05,74.93 105.41,74.3 88.27,74.3 v87.63,73.66 | v147.96,105.41 169.54,105.41 170.81,106.68 IC46.2 176.53,106.68 177.8,105.41 184.78,105.41 v186.06,104.14 | v147.96,91.44 IC1.7 | v187.32,41.91 194.31,41.91 196.85,39.37 210.82,39.37 212.09,38.1 IC38.15 | v132.72,82.55 150.5,82.55 151.13,83.19 176.53,83.19 179.07,80.64 v188.59,80.64
DX9  (via drill 0.61)
  Top 0.254: v201.29,97.79 201.29,81.92 v201.93,81.28 202.56,80.64 202.56,46.35 201.29,45.09 201.29,43.81 IC38.13 | IC6.16 62.87,57.78 v62.87,72.39 64.77,74.3 v64.77,96.52 | v149.22,81.28 146.69,83.82 146.69,92.08 IC1.6
  Bottom 0.254: v201.29,97.79 185.42,97.79 184.15,96.52 IC46.15 | v62.87,72.39 63.5,71.75 71.12,71.75 SV1.17 | 127,95.25 128.27,93.98 IC5.7 | 127,95.25 123.19,99.06 IC27.16 120.65,99.06 119.38,100.33 109.22,100.33 107.95,99.06 IC37.16 105.41,99.06 104.14,100.33 97.79,100.33 96.52,99.06 IC32.16 88.9,99.06 87.63,97.79 66.04,97.79 v64.77,96.52 | 127,95.25 138.43,95.25 139.06,94.61 142.88,94.61 143.51,93.98 IC1.6 | v201.93,81.28 201.29,80.64 189.87,80.64 188.59,79.38 187.96,79.38 187.32,80.01 178.44,80.01 175.9,82.55 151.76,82.55 150.5,81.28 v149.22,81.28
DX10  (via drill 0.61)
  Top 0.254: v200.03,81.92 201.93,80.01 201.93,46.99 IC38.12 | v66.04,58.42 66.04,62.23 67.31,63.5 67.31,73.03 v66.67,73.66 66.04,74.3 v66.04,99.06 | v149.22,83.82 149.22,97.16 148.59,97.79 148.59,104.78 149.22,105.41 147.96,106.68 146.69,106.68 146.69,103.5 IC1.3
  Bottom 0.254: IC46.13 184.15,91.44 184.78,90.81 188.59,90.81 189.23,90.17 203.84,90.17 207.65,86.36 207.65,81.92 202.56,81.92 201.93,82.55 200.66,82.55 v200.03,81.92 198.75,83.19 181.61,83.19 180.34,81.92 179.07,81.92 177.16,83.82 v149.22,83.82 | v66.04,58.42 IC6.17 | v66.67,73.66 SV1.15 | IC1.3 143.51,101.6 142.24,102.87 132.08,102.87 130.81,101.6 IC5.4 IC27.17 119.38,101.6 118.11,102.87 109.22,102.87 107.95,101.6 IC37.17 104.78,101.6 103.5,102.87 97.79,102.87 96.52,101.6 IC32.17 88.27,101.6 87,100.33 67.31,100.33 v66.04,99.06
DX11  (via drill 0.61)
  Top 0.254: v184.15,45.72 v184.15,78.11 184.15,85.09 IC46.11 | v67.31,60.96 67.94,61.59 67.94,75.56 v67.31,76.2 | v69.85,102.23 70.48,101.6 70.48,95.25 69.85,94.61 69.85,78.11 71.12,76.83 SV1.13 | v157.48,101.6 v157.48,78.74
  Bottom 0.254: v184.15,45.72 185.42,44.45 195.58,44.45 196.85,45.72 IC38.11 | v67.31,60.96 IC6.18 | SV1.13 v67.31,76.2 | v69.85,102.23 70.48,102.87 85.72,102.87 87,104.14 IC32.18 92.71,104.14 93.34,104.78 97.16,104.78 97.79,105.41 102.23,105.41 103.5,104.14 IC37.18 107.95,104.14 109.22,105.41 117.47,105.41 118.75,104.14 IC27.18 IC5.3 130.81,104.14 132.08,105.41 142.24,105.41 143.51,104.14 IC1.2 146.05,104.14 147.32,102.87 156.21,102.87 v157.48,101.6 | v184.15,78.11 183.51,78.74 v157.48,78.74
EMA0  (via drill 0.61)
  Top 0.254: v133.99,57.15 134.62,57.78 v134.62,71.12 134.62,74.3 v133.99,74.93 | v78.74,50.8 81.92,53.98 v81.92,73.66
  Bottom 0.254: v133.99,57.15 124.46,57.15 123.19,55.88 IC19.16 | v134.62,71.12 IC39.1 180.97,71.12 182.25,72.39 195.58,72.39 196.85,71.12 IC38.1 | v81.92,73.66 83.82,75.56 104.14,75.56 104.78,76.2 131.44,76.2 132.72,74.93 v133.99,74.93 | v78.74,50.8 SV1.34
EMA1  (via drill 0.61)
  Top 0.254: v193.68,76.2 193.68,67.94 191.77,66.04 IC39.26 | v103.5,69.85 102.23,68.58 102.23,52.7 v102.87,52.07
  Bottom 0.254: IC39.26 191.77,66.04 192.41,65.41 196.22,65.41 196.85,64.77 210.82,64.77 212.09,66.04 IC38.26 | IC19.15 120.65,53.34 119.38,52.07 v102.87,52.07 75.56,52.07 74.3,53.34 SV1.32 | v193.68,76.2 193.04,75.56 179.07,75.56 177.16,73.66 171.45,73.66 170.81,74.3 169.54,73.03 144.15,73.03 142.88,74.3 140.97,74.3 139.06,72.39 135.89,72.39 135.25,73.03 127,73.03 123.83,69.85 v103.5,69.85
EMA2  (via drill 0.61)
  Top 0.254: v81.92,44.45 78.11,40.64 78.11,38.1 76.2,36.2 74.93,36.2 74.93,41.27 75.56,41.91 75.56,53.34 73.66,55.24 SV1.30 | v177.16,64.77 177.16,66.67 IC39.2 | v101.6,69.22 101.6,45.09 v102.23,44.45
  Bottom 0.254: IC39.2 176.53,68.58 177.16,69.22 188.59,69.22 189.23,69.85 194.31,69.85 195.58,68.58 IC38.2 | v81.92,44.45 v102.23,44.45 115.57,44.45 116.84,45.72 IC19.12 | v177.16,64.77 171.45,64.77 168.91,67.31 160.66,67.31 158.12,69.85 135.89,69.85 135.25,69.22 104.14,69.22 103.5,68.58 102.23,68.58 v101.6,69.22
ERROR
  Top 0.254: 59.05,61.59 59.05,57.78 59.69,57.15 59.05,56.52 59.05,55.24 59.69,54.61 59.05,53.98 59.05,42.55 62.87,38.73 62.87,19.05 59.69,19.05 IC10.6 | 59.05,61.59 IC6.19 | 59.05,61.59 59.05,66.67 60.96,68.58 60.96,80.64 59.05,82.55 59.05,104.78 IC9.19
ERROR\
  Top 0.254: IC10.5 52.7,15.88 52.7,17.14 IC10.4 52.7,18.41 52.7,19.68 IC10.3
  Bottom 0.254: IC11.4 82.55,17.78 81.28,19.05 55.88,19.05 54.61,20.32 IC10.3
FLD0  (via drill 0.61)
  Top 0.254: v125.73,58.42 127,57.15 127,48.26 IC21.9 | v133.99,48.26 133.35,47.62 v133.35,45.72 | v142.88,55.88 142.24,55.24 v142.24,53.34
  Bottom 0.254: v125.73,58.42 IC19.17 | v133.99,48.26 134.62,48.26 IC21.14 139.7,50.8 v142.24,53.34 | IC21.9 v133.35,45.72 | v142.88,55.88 RN3.2
FLD1  (via drill 0.61)
  Top 0.254: v149.22,57.15 149.22,55.24 RN3.3 | v133.99,55.88 133.99,50.8 IC21.7
  Bottom 0.254: IC19.14 IC21.7 | v149.22,57.15 139.7,57.15 138.43,55.88 IC21.16 v133.99,55.88
FLD2  (via drill 0.61)
  Top 0.254: v125.73,48.26 v125.73,55.88 | v145.41,60.96 145.41,52.7 RN3.4 | v132.72,55.88 v132.72,60.96
  Bottom 0.254: IC19.13 v125.73,48.26 | v125.73,55.88 IC21.5 v132.72,55.88 | v145.41,60.96 IC21.18 v132.72,60.96
GND  (via drill 0.61)
  Top 0.254: IC29.7 IC5.1 125.73,105.41 125.73,92.08 126.36,91.44 126.36,80.64 121.92,76.2 121.92,68.58 v119.38,66.04 120.02,65.41 120.02,62.87 IC19.18 | v210.82,127 211.46,127.64 211.46,135.25 IC18.12 | IC47.10 188.59,88.27 188.59,89.53 IC47.8 | IC46.10 177.16,88.27 177.16,89.53 IC46.8 | IC48.10 158.12,88.27 158.12,89.53 IC48.8 | 154.31,87.63 154.31,94.61 IC1.12 | v153.67,87 154.31,87.63 | v149.86,64.77 149.86,60.96 RN3.1 | v153.67,65.41 154.31,66.04 154.31,87.63 | IC4.8 83.19,123.83 83.19,111.12 81.92,109.86 81.92,108.58 IC32.2 83.19,106.05 83.19,104.78 IC32.3 83.19,103.5 83.19,102.23 IC32.4 81.92,99.69 81.92,93.34 IC32.8 83.19,90.81 83.19,89.53 IC32.9 83.19,88.27 83.19,87 IC32.10 85.72,84.45 85.72,65.41 IC33.2 83.19,62.87 83.19,61.59 IC33.3 83.19,60.33 83.19,59.05 IC33.4 83.19,57.78 83.19,56.52 IC33.5 83.19,55.24 83.19,53.98 IC33.6 83.19,52.7 83.19,51.44 IC33.7 83.19,50.16 83.19,48.9 IC33.8 83.19,47.62 83.19,46.35 IC33.9 83.19,45.09 83.19,43.81 IC33.10 | IC37.10 98.42,87 98.42,88.27 IC37.9 | IC19.1 113.67,66.67 113.67,85.72 IC27.10 113.67,87 113.67,88.27 IC27.9 | v55.88,119.38 53.34,121.92 IC8.7 | IC12.7 3.81,107.95 3.81,97.79 IC31.7 6.35,93.98 6.35,60.33 7.62,59.05 QG2.7 7.62,57.78 8.26,57.15 v8.26,55.88 | v65.41,133.99 66.67,132.72 66.67,121.28 IC42.10 | IC34.15 167,22.23 167,20.95 IC34.14 167,19.68 167,18.41 IC34.13 172.72,22.86 172.72,26.67 | 172.72,26.67 172.72,35.56 IC39.14 | v161.29,38.73 161.29,46.99 IC15.7 | v42.55,55.88 42.55,62.87 RN1.1 46.35,66.67 v46.35,86.36 | IC7.8 24.77,9.53 24.77,13.34 IC7.5 22.23,15.88 22.23,17.14 IC7.4 | 51.44,10.79 46.99,15.24 IC3.12 43.81,17.14 43.81,18.41 40.01,22.23 40.01,53.98 CPU.26
  Top 0.254: 51.44,10.79 52.07,10.16 IC10.7 | 51.44,10.79 v48.26,7.62 | SV1.39 SV1.37 | IC30.10 98.42,43.81 98.42,45.09 IC30.9 98.42,46.35 98.42,47.62 IC30.8 98.42,48.9 98.42,50.16 IC30.7 98.42,51.44 98.42,52.7 IC30.6 98.42,53.98 98.42,55.24 IC30.5 98.42,56.52 98.42,57.78 IC30.4 | IC24.2 113.67,23.5 113.67,24.77 IC24.1 113.03,25.4 113.03,41.91 IC19.10 | IC11.7 81.92,12.06 81.92,20.95 IC11.2 | IC28.1 98.42,24.77 98.42,23.5 IC28.2 100.97,20.95 100.97,7.62 | 100.97,7.62 IC28.8 | 100.97,7.62 IC28.9 106.05,8.26 106.05,9.53 IC28.10 106.05,10.79 106.05,12.06 IC28.11 | IC41.8 174.62,8.26 174.62,9.53 IC41.7 177.16,12.06 177.16,26.67 172.72,26.67 | IC25.2 144.15,23.5 144.15,24.77 IC25.1 | IC25.8 IC25.9 151.76,8.26 151.76,9.53 IC25.10 151.76,10.79 151.76,12.06 IC25.11 150.5,14.61 v150.5,24.13 | IC21.8 131.44,46.35 131.44,45.09 IC21.10 127,40.64 127,35.56 125.09,33.66 125.09,18.41 125.73,17.78 125.73,16.51 IC24.11 121.28,12.06 121.28,10.79 IC24.10 121.28,9.53 121.28,8.26 IC24.9
  Bottom 0.254: IC17.7 115.57,127 116.84,128.27 127,128.27 128.27,127 IC29.7 130.81,127 131.44,127.64 133.35,127.64 133.99,128.27 138.43,128.27 139.7,127 IC36.7 149.86,127 151.13,128.27 157.48,128.27 158.75,127 IC35.7 161.29,127 161.93,126.36 165.74,126.36 167.64,124.46 IC14.8 176.53,124.46 177.8,125.73 187.96,125.73 189.23,127 IC26.7 191.77,127 193.04,125.73 203.2,125.73 204.47,127 IC18.7 v210.82,127 | IC18.2 207.01,139.7 209.55,137.16 IC18.12 | IC20.7 204.47,91.44 203.84,92.08 200.03,92.08 199.39,92.71 193.04,92.71 191.77,91.44 IC47.8 | RN3.1 IC21.17 | 172.72,87.63 173.99,86.36 IC46.10 | 172.72,87.63 162.56,87.63 161.29,86.36 IC48.10 154.31,86.36 v153.67,87 139.06,87 138.43,87.63 134.62,87.63 133.35,86.36 IC5.10 124.46,86.36 123.19,87.63 116.84,87.63 | v149.86,64.77 150.5,65.41 v153.67,65.41 | 172.72,87.63 187.96,87.63 189.23,86.36 IC47.10 | IC4.8 85.09,124.46 86.36,123.19 95.25,123.19 96.52,124.46 IC13.8 | v119.38,66.04 IC19.1 | 116.84,87.63 115.57,88.9 IC27.9 | 116.84,87.63 105.41,87.63 104.78,88.27 100.97,88.27 100.33,88.9 IC37.9 | IC32.10 85.09,86.36 86.36,85.09 95.25,85.09 96.52,86.36 IC37.10 | IC2.12 46.99,132.08 48.26,133.35 64.77,133.35 v65.41,133.99 67.31,135.89 73.66,135.89 74.93,137.16 IC42.18 | IC12.7 24.13,127 25.4,128.27 50.8,128.27 52.07,127 IC8.7 | v55.88,119.38 IC42.10 | v161.29,38.73 161.93,38.1 IC39.14 178.44,38.1 179.71,39.37 195.58,39.37 196.85,38.1 IC38.14 | v42.55,55.88 CPU.26 CPU.15 v8.26,55.88 | v46.35,86.36 IC9.10 | IC10.7 54.61,10.16 55.88,8.89 66.04,8.89 67.31,10.16 IC40.7 69.85,10.16 70.48,9.53 74.3,9.53 74.93,8.89 81.28,8.89 82.55,10.16 IC11.7
  Bottom 0.254: v48.26,7.62 46.99,6.35 25.4,6.35 24.13,7.62 IC7.8 | IC6.10 54.61,43.18 55.88,44.45 69.22,44.45 70.48,45.72 SV1.37 | IC33.10 82.55,43.18 81.28,41.91 73.03,41.91 71.75,43.18 SV1.39 | IC30.10 100.33,43.18 101.6,41.91 111.76,41.91 113.03,43.18 IC19.10 | IC28.9 IC24.8 IC24.9 | 96.52,24.13 86.36,24.13 85.09,22.86 IC11.2 | 96.52,24.13 97.79,25.4 IC28.1 | IC23.7 204.47,10.16 203.84,9.53 200.03,9.53 199.39,8.89 193.04,8.89 191.77,10.16 IC22.7 189.23,10.16 187.96,11.43 177.8,11.43 176.53,10.16 IC41.7 173.99,10.16 172.72,8.89 166.37,8.89 165.1,7.62 IC34.8 IC25.9 | v150.5,24.13 147.32,24.13 146.05,22.86 IC25.2 | IC24.10 IC16.7 131.44,10.16 132.72,8.89 142.24,8.89 143.51,7.62 IC25.8 | 96.52,24.13 107.95,24.13 108.58,24.77 112.39,24.77 113.03,25.4 IC24.1 | IC33.5 85.09,55.88 86.36,54.61 92.71,54.61 93.98,55.88 IC30.5
GTF\  (via drill 0.61)
  Top 0.254: v125.73,130.81 127,132.08 127,139.7 IC29.1 | v133.99,142.88 133.99,148.59 156.21,148.59 161.93,142.88 161.93,136.53 IC35.4
  Bottom 0.254: v125.73,130.81 109.22,130.81 107.95,129.54 IC13.11 | v133.99,142.88 133.35,142.24 IC29.1
HLT\
  Bottom 0.254: IC4.13 90.17,134.62 88.9,135.89 82.55,135.89 77.47,140.97 59.69,140.97 58.42,142.24 IC8.1
IFETCH  (via drill 0.61)
  Top 0.254: v163.19,55.88 v163.19,50.8 162.56,50.16 v162.56,45.72 | v187.32,50.16 188.59,48.9 188.59,19.68 IC22.4 | 57.78,46.99 57.78,53.98 56.52,55.24 56.52,80.01 v57.15,80.64 | 57.78,46.99 57.78,20.32 IC10.12 | 57.78,46.99 v57.15,46.99
  Bottom 0.254: v163.19,55.88 IC15.4 | v163.19,50.8 IC15.9 168.91,50.8 170.18,49.53 186.69,49.53 v187.32,50.16 | v57.15,80.64 56.52,81.28 CPU.36 | v162.56,45.72 139.7,45.72 138.43,46.99 128.27,46.99 125.73,49.53 119.38,49.53 116.84,46.99 v57.15,46.99
IFLD0  (via drill 0.61)
  Top 0.254: 116.2,64.77 116.2,92.08 IC27.7 | 116.2,64.77 v116.2,49.53 116.2,17.14 | 116.2,17.14 IC24.5 | v165.74,3.17 165.74,10.79 IC34.11 | v123.83,3.17 116.2,10.79 116.2,17.14 | v80.01,127 81.92,125.09 v81.92,119.38 | v109.22,118.11 110.49,116.84 110.49,100.97 109.22,99.69 109.22,93.34 111.12,91.44 111.12,66.67 113.03,64.77 116.2,64.77
  Bottom 0.254: v165.74,3.17 165.1,2.54 124.46,2.54 v123.83,3.17 | v116.2,49.53 118.11,49.53 120.65,52.07 127,52.07 128.27,53.34 IC21.6 | v81.92,119.38 93.98,119.38 95.25,118.11 v109.22,118.11 | v80.01,127 IC42.14
IFLD1  (via drill 0.61)
  Top 0.254: v118.11,59.69 118.11,61.59 118.75,62.23 118.75,63.5 117.47,64.77 117.47,97.16 118.11,97.79 116.84,99.06 116.2,99.06 116.2,98.42 IC27.6 | v78.74,120.02 78.74,121.92 IC42.13 | v109.22,119.38 111.12,117.47 111.12,100.33 109.86,99.06 109.86,97.79 v111.12,96.52 | v177.8,55.24 177.8,46.99 173.35,46.99 171.45,45.09 172.09,44.45 172.09,24.13 166.37,24.13 161.93,19.68 161.93,17.14 IC34.5
  Bottom 0.254: IC24.4 115.57,17.78 116.2,17.14 120.02,17.14 120.65,16.51 156.84,16.51 158.12,15.24 IC34.5 | v118.11,59.69 127,59.69 128.27,58.42 IC21.4 131.44,58.42 132.72,59.69 148.59,59.69 151.13,57.15 163.19,57.15 165.74,54.61 177.16,54.61 v177.8,55.24 | v78.74,120.02 79.38,120.65 93.98,120.65 95.25,119.38 v109.22,119.38 | IC27.6 v111.12,96.52
IFLD2  (via drill 0.61)
  Top 0.254: v112.39,62.23 112.39,22.23 IC24.3 | v116.84,97.79 116.84,62.87 v117.47,62.23 | v109.86,122.56 111.76,120.65 111.76,99.69 v111.12,99.06
  Bottom 0.254: IC24.3 115.57,20.32 116.2,19.68 120.02,19.68 120.65,19.05 161.29,19.05 161.93,19.68 161.93,22.23 160.66,22.23 IC34.2 | v112.39,62.23 v117.47,62.23 123.19,62.23 123.83,62.87 127.64,62.87 128.27,63.5 IC21.2 | v116.84,97.79 115.57,99.06 IC27.5 v111.12,99.06 | v109.86,122.56 104.14,122.56 103.5,123.19 96.52,123.19 95.89,122.56 85.72,122.56 85.09,123.19 71.12,123.19 69.85,124.46 IC42.8
INHIBIT  (via drill 0.61)
  Top 0.254: v126.36,28.57 v126.36,22.86 | v100.97,28.57 100.97,61.59 IC30.2 | v169.54,29.84 169.54,59.05 IC15.13 | v217.81,130.81 219.71,128.91 219.71,34.29 v216.53,31.11
  Bottom 0.254: 125.73,27.94 v126.36,28.57 | 125.73,27.94 101.6,27.94 v100.97,28.57 | v126.36,22.86 IC16.2 | 168.28,28.57 v169.54,29.84 | 168.28,28.57 142.24,28.57 141.6,29.21 134.62,29.21 133.35,27.94 125.73,27.94 | v217.81,130.81 208.28,130.81 207.01,132.08 IC18.5 | v216.53,31.11 214.63,29.21 181.61,29.21 180.97,29.84 172.09,29.84 170.81,28.57 168.28,28.57
INTCLR  (via drill 0.61)
  Top 0.254: v192.41,125.09 192.41,127.64 IC26.6 | v210.82,125.09 214.63,121.28 214.63,113.03 215.26,112.39 215.26,78.74 214.63,78.11 214.63,72.39 215.9,71.12 v215.9,59.05 | v218.44,45.72 216.53,43.81 v216.53,32.38 | v170.81,29.84 170.18,29.21 v170.18,25.4
  Bottom 0.254: IC28.15 107.95,22.86 109.22,24.13 118.75,24.13 120.02,22.86 IC24.15 125.09,22.86 126.36,21.59 146.05,21.59 146.69,22.23 150.5,22.23 151.13,22.86 IC25.15 153.67,22.86 154.94,24.13 168.91,24.13 v170.18,25.4 | v210.82,125.09 v192.41,125.09 | v215.9,59.05 219.07,55.88 219.07,45.72 v218.44,45.72 | v216.53,32.38 214,29.84 182.25,29.84 181.61,30.48 171.45,30.48 v170.81,29.84
INTCLR\  (via drill 0.61)
  Top 0.254: v80.64,22.86 81.28,22.23 v81.28,6.99 | v141.6,6.99 143.51,8.89 148.59,8.89 148.59,41.27 v147.96,41.91 | v177.8,41.91 179.07,43.18 179.07,71.75 v178.44,72.39 | IC26.3 189.87,136.53 189.87,135.25 IC26.4
  Bottom 0.254: v81.28,6.99 97.16,6.99 97.79,6.35 140.97,6.35 v141.6,6.99 | v147.96,41.91 148.59,42.55 169.54,42.55 170.81,41.27 173.35,41.27 173.99,41.91 v177.8,41.91 | v178.44,72.39 180.97,72.39 181.61,73.03 217.17,73.03 218.44,74.3 218.44,111.12 214,111.12 212.72,112.39 212.72,114.94 215.9,114.94 219.71,118.75 219.71,133.35 193.04,133.35 191.77,134.62 IC26.4 | v80.64,22.86 IC40.13
INTGNT  (via drill 0.61)
  Top 0.254: IC42.11 v76.2,114.3 76.2,89.53 73.66,87 SV1.6 | v125.09,147.32 125.09,151.13 180.34,151.13 189.23,142.24 IC26.1 | v108.58,146.69 102.23,140.34 102.23,113.67 104.14,111.76 105.41,111.76 v105.41,113.03
  Bottom 0.254: CPU.39 39.37,88.9 40.01,88.27 47.62,88.27 48.26,87.63 71.75,87.63 73.03,86.36 SV1.6 | v125.09,147.32 124.46,146.69 v108.58,146.69 | v105.41,113.03 104.14,114.3 81.28,114.3 80.64,113.67 76.83,113.67 v76.2,114.3
IO_RESET\  (via drill 0.61)
  Top 0.254: v136.53,123.83 139.06,126.36 139.06,130.18 IC29.10 | v104.14,123.83 v104.14,113.03 | v70.48,113.03 67.31,109.86 67.31,83.19 66.67,82.55 66.67,79.38 v67.31,78.74
  Bottom 0.254: v136.53,123.83 135.89,124.46 110.49,124.46 109.22,123.19 104.78,123.19 v104.14,123.83 | v104.14,113.03 103.5,113.67 81.92,113.67 81.28,113.03 v70.48,113.03 | v67.31,78.74 SV1.11
IOT\  (via drill 0.61)
  Top 0.254: 8.89,100.33 9.53,99.69 9.53,5.08 28.57,5.08 29.21,5.71 29.21,6.35 IC7.9 | 8.89,100.33 6.35,100.33 5.71,100.97 5.71,102.23 IC31.3 | v54.61,124.46 55.24,125.09 55.24,130.18 IC8.5 | v24.77,123.19 10.16,108.58 10.16,101.6 8.89,100.33
  Bottom 0.254: v54.61,124.46 53.34,123.19 v24.77,123.19
IR0
  Bottom 0.254: IC7.3 28.57,14.61 28.57,8.89 43.18,8.89 44.45,7.62 IC3.9
IR1
  Bottom 0.254: IC7.2 20.95,20.95 20.95,6.99 22.23,5.71 47.62,5.71 49.53,7.62 49.53,9.53 46.35,9.53 IC3.10
IR2
  Bottom 0.254: IC7.1 24.13,25.4 25.4,24.13 31.75,24.13 32.38,24.77 36.2,24.77 36.83,24.13 42.55,24.13 43.81,22.86 IC3.15
IR3  (via drill 0.61)
  Top 0.254: v41.91,27.94 44.45,25.4 IC3.16 | v19.05,31.11 v19.05,97.79 | v56.52,107.95 57.15,108.58 v57.15,130.18
  Bottom 0.254: v41.91,27.94 38.73,31.11 v19.05,31.11 | v19.05,97.79 29.21,107.95 v56.52,107.95 | v57.15,130.18 57.78,130.81 81.28,130.81 82.55,129.54 IC4.6
IR3\
  Top 0.254: IC3.1 32.38,31.11 32.38,135.25 IC12.12
  Bottom 0.254: IC8.13 59.69,139.7 58.42,140.97 35.56,140.97 31.75,137.16 IC12.12
IR4  (via drill 0.61)
  Top 0.254: v48.9,134.62 48.9,124.46 IC2.9
  Bottom 0.254: v48.9,134.62 50.16,135.89 58.42,135.89 59.69,137.16 IC8.12
IR4\
  Bottom 0.254: IC2.8 36.83,124.46 35.56,125.73 21.59,125.73 20.95,126.36 20.95,133.35 24.13,133.35 25.4,134.62 IC12.11
IR5\
  Bottom 0.254: IC12.6 24.13,129.54 25.4,130.81 43.18,130.81 44.45,129.54 IC2.11 46.99,129.54 48.26,130.81 54.61,130.81 55.24,131.44 59.05,131.44 59.69,132.08 IC8.10
IR6  (via drill 0.61)
  Top 0.254: v187.32,135.25 188.59,133.99 v188.59,114.94 188.59,98.42 IC47.6 | v47.62,125.73 47.62,137.79 IC2.15 | v116.2,122.56 v110.49,128.27 | v147.32,122.56 150.5,119.38 v150.5,116.84
  Bottom 0.254: IC47.6 IC47.15 | v187.32,135.25 184.15,138.43 177.8,138.43 176.53,137.16 IC14.3 | v47.62,125.73 64.77,125.73 67.31,128.27 v110.49,128.27 | v116.2,122.56 116.84,121.92 137.16,121.92 137.79,121.28 146.05,121.28 v147.32,122.56 | v150.5,116.84 151.13,116.2 160.66,116.2 161.93,117.47 173.99,117.47 175.9,115.57 187.96,115.57 v188.59,114.94
IR6\
  Bottom 0.254: IC12.5 24.13,132.08 25.4,133.35 31.75,133.35 36.83,138.43 39.37,138.43 40.64,137.16 IC2.14
IR7  (via drill 0.61)
  Top 0.254: v194.94,100.97 v194.94,91.44 | v179.07,101.6 179.07,135.89 IC14.2 | v50.16,146.05 50.16,145.41 46.99,142.24 IC2.16 | v75.56,146.69 81.28,140.97 v81.28,139.7
  Bottom 0.254: v194.94,100.97 194.31,101.6 IC47.4 189.23,101.6 187.96,100.33 180.34,100.33 v179.07,101.6 | v194.94,91.44 IC47.13 | v50.16,146.05 51.44,147.32 61.59,147.32 62.23,146.69 v75.56,146.69 | v81.28,139.7 82.55,138.43 172.72,138.43 173.99,139.7 IC14.2
IR7\
  Bottom 0.254: IC12.4 29.21,140.97 34.29,140.97 35.56,142.24 IC2.1
IR8  (via drill 0.61)
  Top 0.254: v193.68,104.78 193.68,90.17 v194.94,88.9 194.94,81.92 v191.77,78.74 | v152.4,81.28 IC1.9 | v172.72,81.28 172.72,147.96 172.09,148.59 172.09,149.86 173.35,149.86 174.62,148.59 174.62,142.88 IC14.1
  Bottom 0.254: v194.94,88.9 195.58,88.9 IC47.11 | v193.68,104.78 191.77,106.68 IC47.2 | v152.4,81.28 153.03,81.92 172.72,81.92 | 172.72,81.92 175.26,81.92 177.8,79.38 186.69,79.38 187.32,78.74 v191.77,78.74 | v172.72,81.28 172.72,81.92
IR8\  (via drill 0.61)
  Top 0.254: v77.47,111.76 76.83,111.12 v76.83,88.9 | v122.56,84.45 123.83,83.19 125.09,83.19 v125.09,87.63
  Bottom 0.254: v77.47,111.76 70.48,111.76 68.58,113.67 20.32,113.67 20.32,134.62 IC12.3 | v76.83,88.9 81.28,84.45 95.89,84.45 96.52,85.09 107.95,85.09 108.58,84.45 v122.56,84.45 | v125.09,87.63 133.35,87.63 135.89,90.17 142.24,90.17 143.51,88.9 IC1.8
IR9  (via drill 0.61)
  Top 0.254: v110.49,135.89 IC17.2 116.2,141.6 116.2,144.78 121.28,149.86 123.83,149.86 123.83,147.32 125.09,146.05 128.27,146.05 131.44,149.22 162.56,149.22 162.56,130.81 | v156.21,91.44 155.57,92.08 155.57,120.65 158.75,123.83 158.75,125.73 158.12,126.36 158.12,130.18 158.75,130.81 162.56,130.81 | 162.56,130.81 v163.83,130.81
  Bottom 0.254: 96.52,135.89 90.17,135.89 89.53,136.53 85.72,136.53 85.09,137.16 IC4.3 | 96.52,135.89 97.79,137.16 IC13.3 | v110.49,135.89 96.52,135.89 | v163.83,130.81 171.45,130.81 172.72,129.54 IC14.6 | v156.21,91.44 IC1.10
IR10  (via drill 0.61)
  Top 0.254: v150.5,111.12 150.5,106.05 IC1.15 | v103.5,111.12 101.6,113.03 101.6,137.16 IC13.2 97.79,139.7 v93.98,143.51 | v87,143.51 87,142.88 IC4.2
  Bottom 0.254: v150.5,111.12 v103.5,111.12 | v93.98,143.51 v87,143.51
IR10\  (via drill 0.61)
  Top 0.254: v149.22,116.84 149.22,111.12 149.86,110.49 149.86,104.14 IC1.14 | v119.38,116.84 v119.38,132.08
  Bottom 0.254: v149.22,116.84 v119.38,116.84 | v119.38,132.08 IC17.5
IR11  (via drill 0.61)
  Top 0.254: v125.09,120.65 124.46,121.28 124.46,132.08 123.19,133.35 117.47,133.35 117.47,130.18 115.57,128.27 111.76,128.27 109.22,130.81 109.22,146.05 109.86,146.69 108.58,147.96 102.87,147.96 102.87,146.05 IC13.1 | v152.4,120.02 IC1.16
  Bottom 0.254: IC4.1 85.09,142.24 86.36,140.97 96.52,140.97 97.79,142.24 IC13.1 | v152.4,120.02 151.76,120.65 147.96,120.65 146.69,119.38 126.36,119.38 v125.09,120.65
IR11\  (via drill 0.61)
  Top 0.254: v123.83,114.94 123.83,130.18 IC17.10 | v144.15,114.3 144.78,113.67 IC1.1
  Bottom 0.254: v123.83,114.94 125.73,113.03 139.06,113.03 140.34,114.3 v144.15,114.3
ISZ\
  Top 0.254: IC7.13 PAD3.1
JMP\
  Bottom 0.254: IC7.10 31.75,10.16 35.56,13.97 58.42,13.97 59.69,12.7 IC10.9
JMP_OR_JMS  (via drill 0.61)
  Top 0.254: v66.04,36.2 65.41,35.56 65.41,10.16 IC10.8 | v102.23,34.92 103.5,36.2 103.5,51.44 104.14,52.07 v104.14,54.61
